(* Logix 5000 AddOnInstructionDefinition export AKD_Two_Axis_Move; software revision 19.01; part 2 of 3 *)

ADD_ON_INSTRUCTION AKD_Set_Position   (* revision 2.1, ExecutePrescan, ExecuteEnableInFalse *)
// Set Drive Position
// Revision note:
// Don't error if Command_Timeout preset is 0
VAR_OUTPUT
   DN : BOOL; {access Read Only, visible}   // Command Successful
   ER : BOOL; {access Read Only, visible}   // Error
END_VAR
VAR_IN_OUT
   Axis : AKD_Axis; {required}
END_VAR
VAR_INPUT
   Incremental : BOOL; {visible}   // Position Definition (0=Absolute, 1=Incremental)
   Position : DINT; {required}   // Position Value
END_VAR
VAR_OUTPUT
   PC : BOOL; {access Read Only, visible}   // Process Complete
   IP : BOOL; {access Read Only, visible}   // In Process
END_VAR
VAR
   Response_Bytes : SINT[8];
   OS_LoadStart : BOOL;
   Position_Internal : DINT;   // Scaled Position Value for Drive
   Command_Timeout : TIMER := (PRE := 200);   // Timeout Timer
   Command_Message_Type : SINT;   // Command Message Type
   Command_Axis_Number : SINT;   // Command Axis Number
   Response_Message_Type : SINT;   // Response Message Type
   Response_Axis_Number : SINT;   // Response Axis Number
   Command_Bytes : SINT[8];
   Step : SINT;
END_VAR

ROUTINE EnableInFalse   (* ladder *)
// EnableIn_False
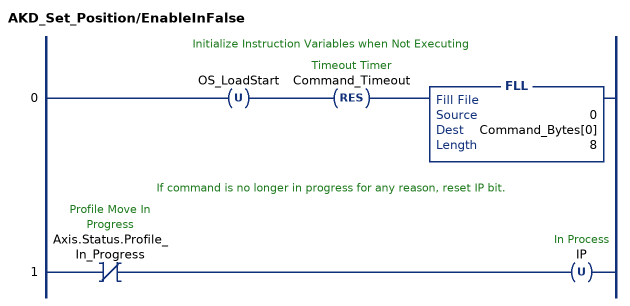
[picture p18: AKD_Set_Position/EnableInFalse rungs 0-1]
   // Initialize Instruction Variables when Not Executing
   0: OTU(OS_LoadStart)RES(Command_Timeout)FLL(0,Command_Bytes[0],8);
   // If command is no longer in progress for any reason, reset IP bit.
   1: XIO(Axis.Status.Profile_In_Progress)OTU(IP);
END_ROUTINE

ROUTINE Logic   (* ladder *)
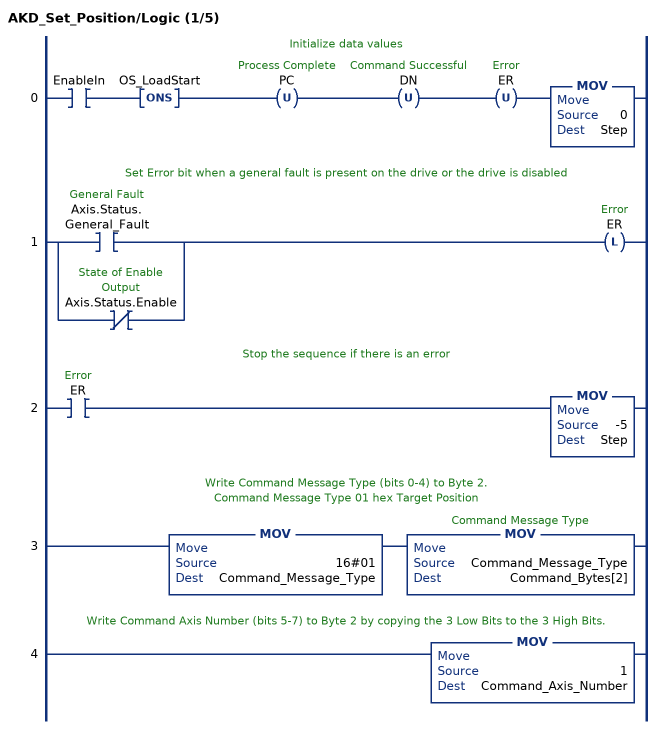
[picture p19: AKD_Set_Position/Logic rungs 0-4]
   // Initialize data values
   0: XIC(EnableIn)ONS(OS_LoadStart)OTU(PC)OTU(DN)OTU(ER)MOV(0,Step);
   // Set Error bit when a general fault is present on the drive or the drive is disabled
   1: [XIC(Axis.Status.General_Fault) ,XIO(Axis.Status.Enable) ]OTL(ER);
   // Stop the sequence if there is an error
   2: XIC(ER)MOV(-5,Step);
   // Write Command Message Type (bits 0-4) to Byte 2.
   // Command Message Type 01 hex Target Position
   3: MOV(16#01,Command_Message_Type)MOV(Command_Message_Type,Command_Bytes[2]);
   // Write Command Axis Number (bits 5-7) to Byte 2 by copying the 3 Low Bits to the 3 High Bits.
   4: MOV(1,Command_Axis_Number);
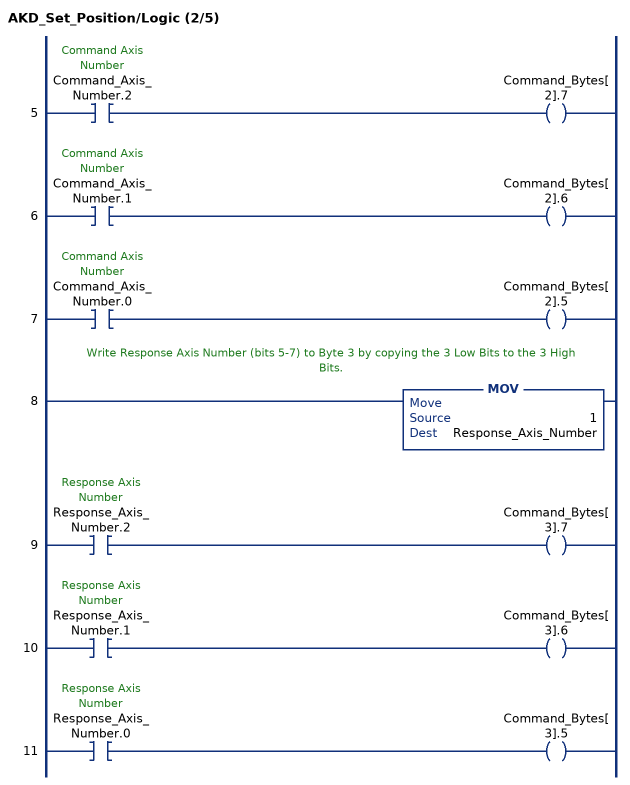
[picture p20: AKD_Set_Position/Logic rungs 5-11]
   5: XIC(Command_Axis_Number.2)OTE(Command_Bytes[2].7);
   6: XIC(Command_Axis_Number.1)OTE(Command_Bytes[2].6);
   7: XIC(Command_Axis_Number.0)OTE(Command_Bytes[2].5);
   // Write Response Axis Number (bits 5-7) to Byte 3 by copying the 3 Low Bits to the 3 High Bits.
   8: MOV(1,Response_Axis_Number);
   9: XIC(Response_Axis_Number.2)OTE(Command_Bytes[3].7);
   10: XIC(Response_Axis_Number.1)OTE(Command_Bytes[3].6);
   11: XIC(Response_Axis_Number.0)OTE(Command_Bytes[3].5);
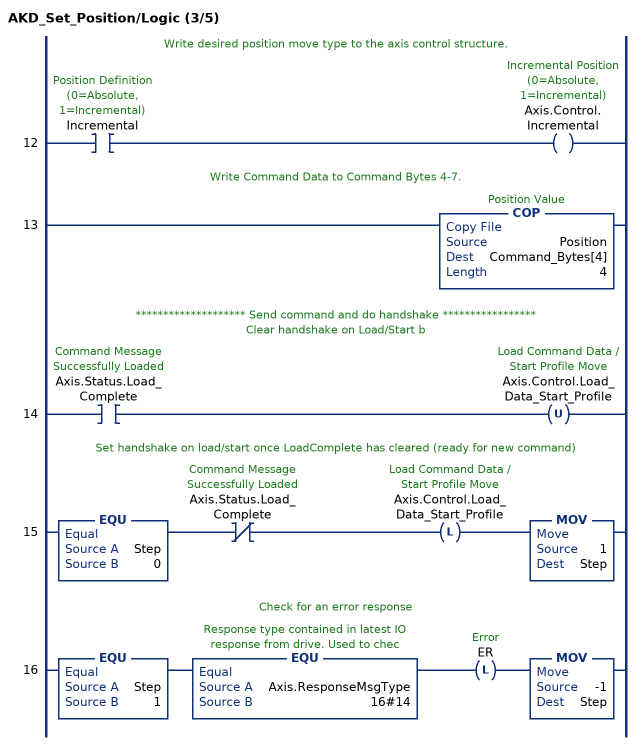
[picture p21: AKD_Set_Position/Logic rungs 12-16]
   // Write desired position move type to the axis control structure.
   12: XIC(Incremental)OTE(Axis.Control.Incremental);
   // Write Command Data to Command Bytes 4-7.
   13: COP(Position,Command_Bytes[4],4);
   // ******************** Send command and do handshake *****************
   // Clear handshake on Load/Start b
   14: XIC(Axis.Status.Load_Complete)OTU(Axis.Control.Load_Data_Start_Profile);
   // Set handshake on load/start once LoadComplete has cleared (ready for new command)
   15: EQU(Step,0)XIO(Axis.Status.Load_Complete)OTL(Axis.Control.Load_Data_Start_Profile)MOV(1,Step);
   // Check for an error response
   16: EQU(Step,1)EQU(Axis.ResponseMsgType,16#14)OTL(ER)MOV(-1,Step);
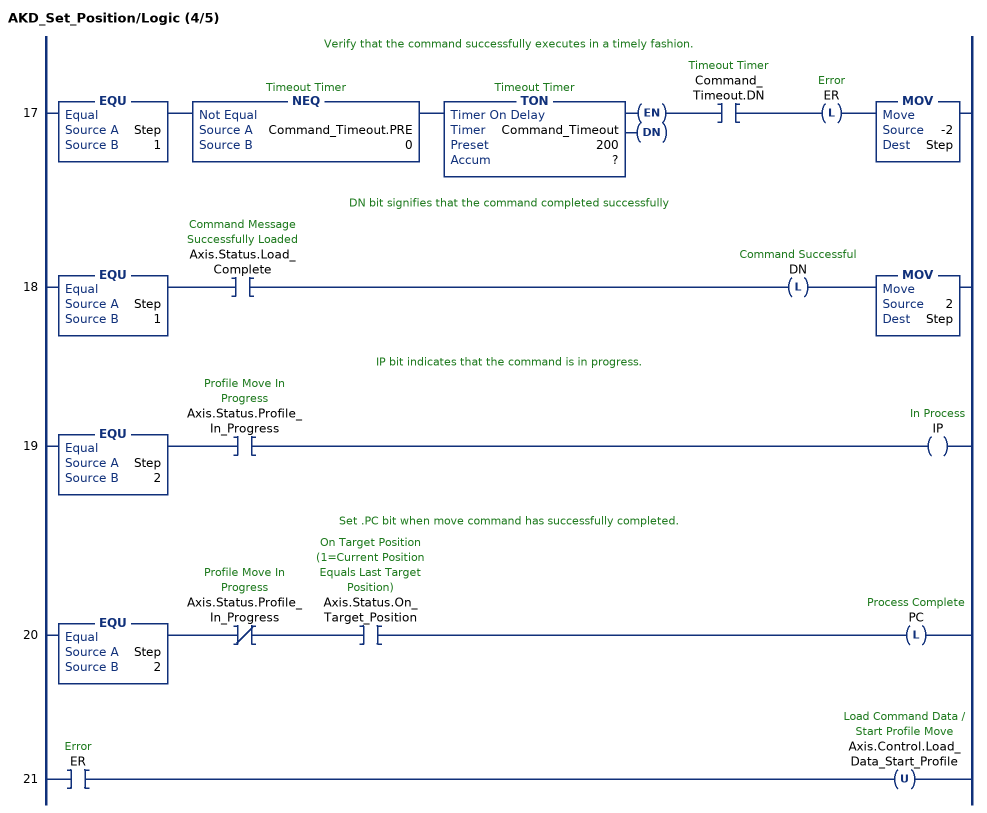
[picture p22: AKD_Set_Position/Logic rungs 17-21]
   // Verify that the command successfully executes in a timely fashion.
   17: EQU(Step,1)NEQ(Command_Timeout.PRE,0)TON(Command_Timeout,?,?)XIC(Command_Timeout.DN)OTL(ER)MOV(-2,Step);
   // DN bit signifies that the command completed successfully
   18: EQU(Step,1)XIC(Axis.Status.Load_Complete)OTL(DN)MOV(2,Step);
   // IP bit indicates that the command is in progress.
   19: EQU(Step,2)XIC(Axis.Status.Profile_In_Progress)OTE(IP);
   // Set .PC bit when move command has successfully completed.
   20: EQU(Step,2)XIO(Axis.Status.Profile_In_Progress)XIC(Axis.Status.On_Target_Position)OTL(PC);
   21: XIC(ER)OTU(Axis.Control.Load_Data_Start_Profile);
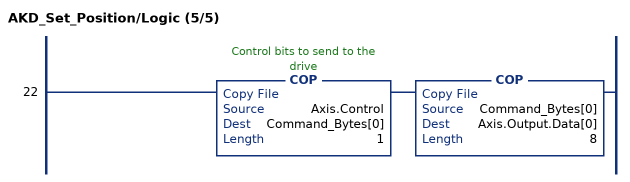
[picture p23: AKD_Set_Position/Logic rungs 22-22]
   22: COP(Axis.Control,Command_Bytes[0],1)COP(Command_Bytes[0],Axis.Output.Data[0],8);
END_ROUTINE

ROUTINE Prescan   (* ladder *)
// Prescan
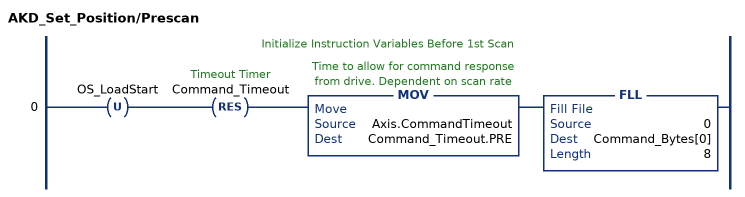
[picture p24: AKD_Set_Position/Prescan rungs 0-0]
   // Initialize Instruction Variables Before 1st Scan
   0: OTU(OS_LoadStart)RES(Command_Timeout)MOV(Axis.CommandTimeout,Command_Timeout.PRE)FLL(0,Command_Bytes[0],8);
END_ROUTINE
END_ADD_ON_INSTRUCTION

ADD_ON_INSTRUCTION AKD_Move   (* revision 3.1, ExecutePrescan, ExecuteEnableInFalse *)
// Motion Axis Move - Position Move
// Revision note:
// Don't error if Command_Timeout preset is 0
VAR_IN_OUT
   Axis : AKD_Axis; {required}
END_VAR
VAR_INPUT
   Move_Type : SINT; {required}   // Move Type (0=Absolute, 1=Incremental)
   Accel : DINT; {required}   // Acceleration
   Decel : DINT; {required}   // Deceleration
   Speed : DINT; {required}   // Move Speed
   Position : DINT; {required}   // Target Position
END_VAR
VAR_OUTPUT
   DN : BOOL; {access Read Only, visible}   // Command Successfully Initiated
   ER : BOOL; {access Read Only, visible}   // Error
   IP : BOOL; {access Read Only, visible}   // Command in Process
   PC : BOOL; {access Read Only, visible}   // Command Process Complete
END_VAR
VAR
   Step : SINT;   // Sequence Step Number
   Command_Axis_Number : SINT;
   Response_Axis_Number : SINT;
   Set_Accel : AKD_Set_Accel;
   Set_Decel : AKD_Set_Decel;
   Set_Velocity : AKD_Set_Velocity;
   OS_Start_Sequence : BOOL;
   Set_Position : AKD_Set_Position;
   Command_Timeout : TIMER := (PRE := 200);
   Command_Bytes : SINT[64];
   ErrorData : SINT[8];
END_VAR

ROUTINE EnableInFalse   (* ladder *)
// EnableIn_False
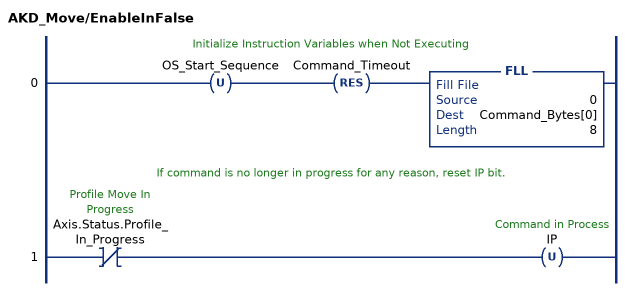
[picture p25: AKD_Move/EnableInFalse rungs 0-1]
   // Initialize Instruction Variables when Not Executing
   0: OTU(OS_Start_Sequence)RES(Command_Timeout)FLL(0,Command_Bytes[0],8);
   // If command is no longer in progress for any reason, reset IP bit.
   1: XIO(Axis.Status.Profile_In_Progress)OTU(IP);
END_ROUTINE

ROUTINE Logic   (* ladder *)
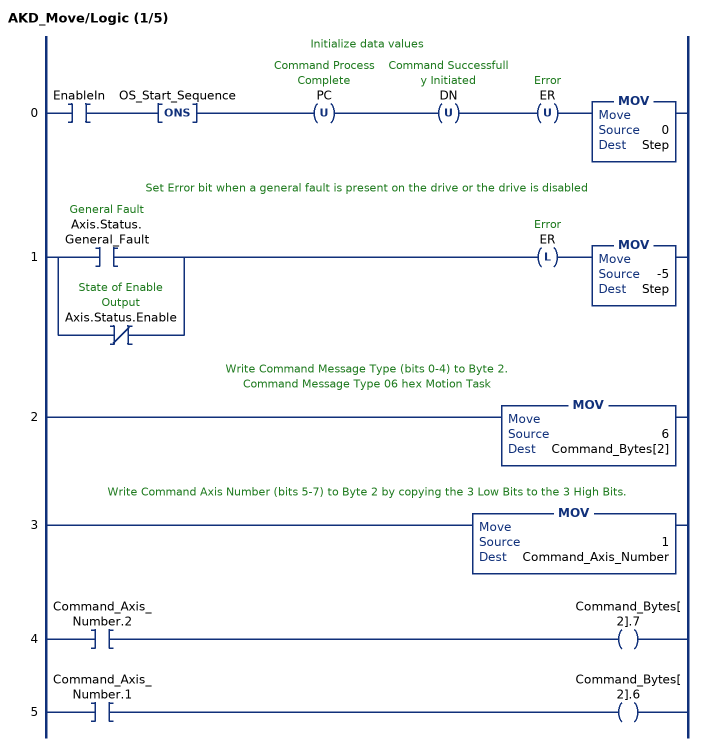
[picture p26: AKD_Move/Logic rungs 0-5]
   // Initialize data values
   0: XIC(EnableIn)ONS(OS_Start_Sequence)OTU(PC)OTU(DN)OTU(ER)MOV(0,Step);
   // Set Error bit when a general fault is present on the drive or the drive is disabled
   1: [XIC(Axis.Status.General_Fault) ,XIO(Axis.Status.Enable) ]OTL(ER)MOV(-5,Step);
   // Write Command Message Type (bits 0-4) to Byte 2.
   // Command Message Type 06 hex Motion Task
   2: MOV(6,Command_Bytes[2]);
   // Write Command Axis Number (bits 5-7) to Byte 2 by copying the 3 Low Bits to the 3 High Bits.
   3: MOV(1,Command_Axis_Number);
   4: XIC(Command_Axis_Number.2)OTE(Command_Bytes[2].7);
   5: XIC(Command_Axis_Number.1)OTE(Command_Bytes[2].6);
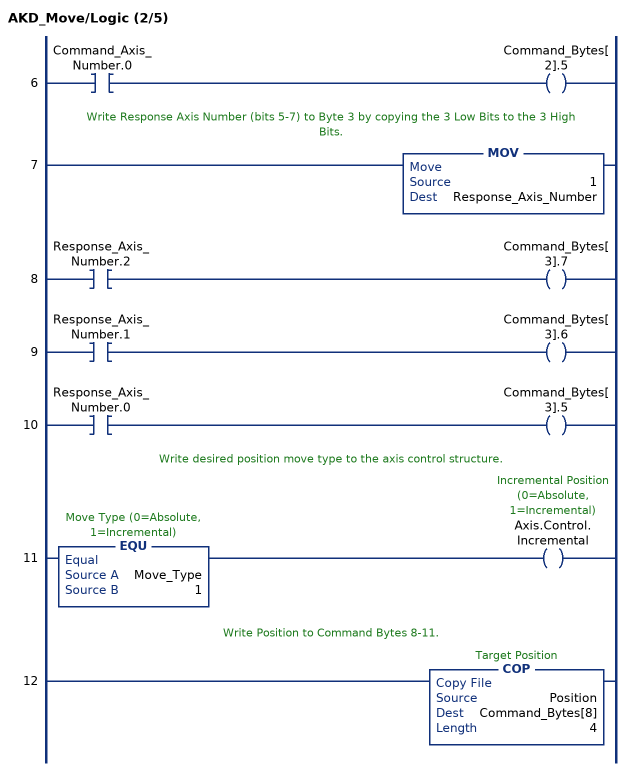
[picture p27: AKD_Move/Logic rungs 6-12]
   6: XIC(Command_Axis_Number.0)OTE(Command_Bytes[2].5);
   // Write Response Axis Number (bits 5-7) to Byte 3 by copying the 3 Low Bits to the 3 High Bits.
   7: MOV(1,Response_Axis_Number);
   8: XIC(Response_Axis_Number.2)OTE(Command_Bytes[3].7);
   9: XIC(Response_Axis_Number.1)OTE(Command_Bytes[3].6);
   10: XIC(Response_Axis_Number.0)OTE(Command_Bytes[3].5);
   // Write desired position move type to the axis control structure.
   11: EQU(Move_Type,1)OTE(Axis.Control.Incremental);
   // Write Position to Command Bytes 8-11.
   12: COP(Position,Command_Bytes[8],4);
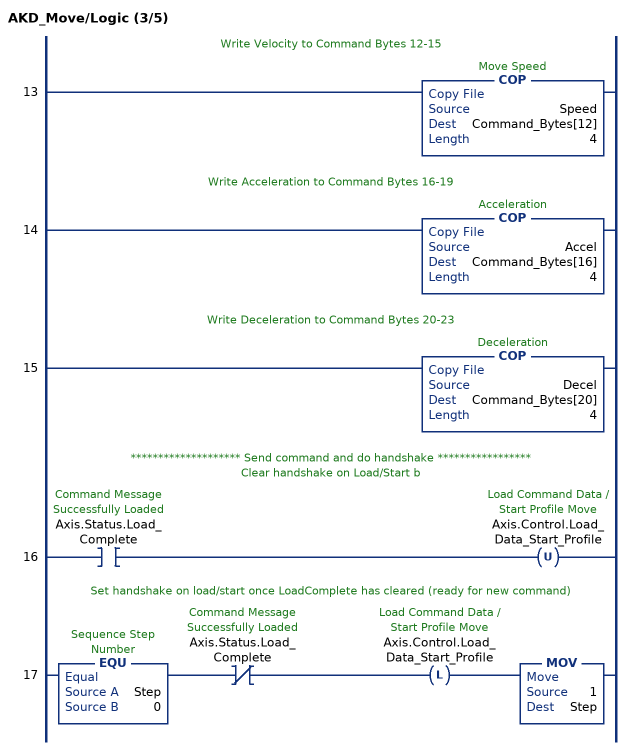
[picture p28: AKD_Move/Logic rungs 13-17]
   // Write Velocity to Command Bytes 12-15
   13: COP(Speed,Command_Bytes[12],4);
   // Write Acceleration to Command Bytes 16-19
   14: COP(Accel,Command_Bytes[16],4);
   // Write Deceleration to Command Bytes 20-23
   15: COP(Decel,Command_Bytes[20],4);
   // ******************** Send command and do handshake *****************
   // Clear handshake on Load/Start b
   16: XIC(Axis.Status.Load_Complete)OTU(Axis.Control.Load_Data_Start_Profile);
   // Set handshake on load/start once LoadComplete has cleared (ready for new command)
   17: EQU(Step,0)XIO(Axis.Status.Load_Complete)OTL(Axis.Control.Load_Data_Start_Profile)MOV(1,Step);
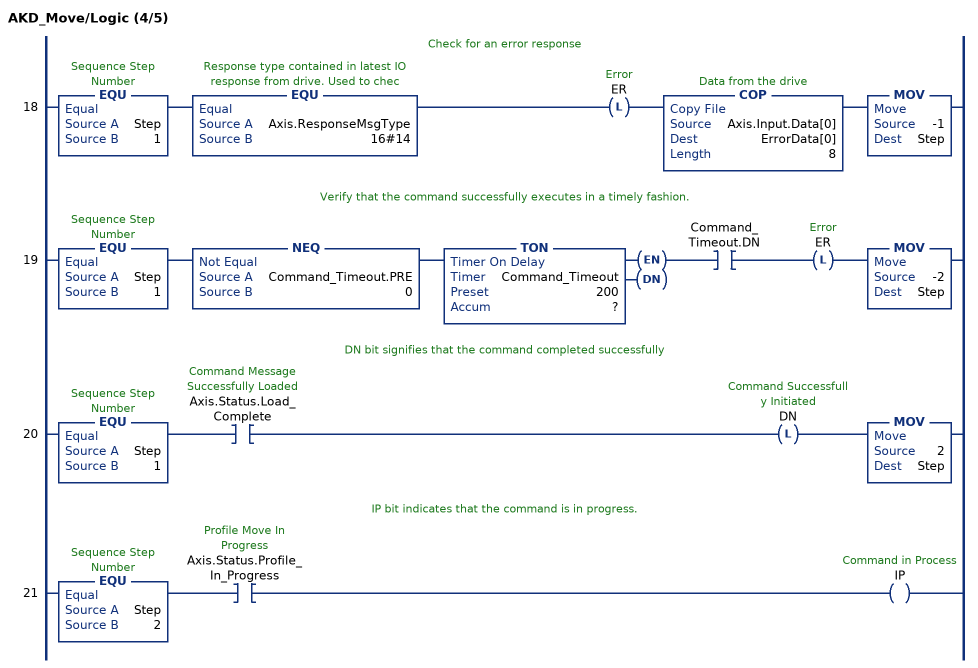
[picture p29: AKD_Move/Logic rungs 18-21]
   // Check for an error response
   18: EQU(Step,1)EQU(Axis.ResponseMsgType,16#14)OTL(ER)COP(Axis.Input.Data[0],ErrorData[0],8)MOV(-1,Step);
   // Verify that the command successfully executes in a timely fashion.
   19: EQU(Step,1)NEQ(Command_Timeout.PRE,0)TON(Command_Timeout,?,?)XIC(Command_Timeout.DN)OTL(ER)MOV(-2,Step);
   // DN bit signifies that the command completed successfully
   20: EQU(Step,1)XIC(Axis.Status.Load_Complete)OTL(DN)MOV(2,Step);
   // IP bit indicates that the command is in progress.
   21: EQU(Step,2)XIC(Axis.Status.Profile_In_Progress)OTE(IP);
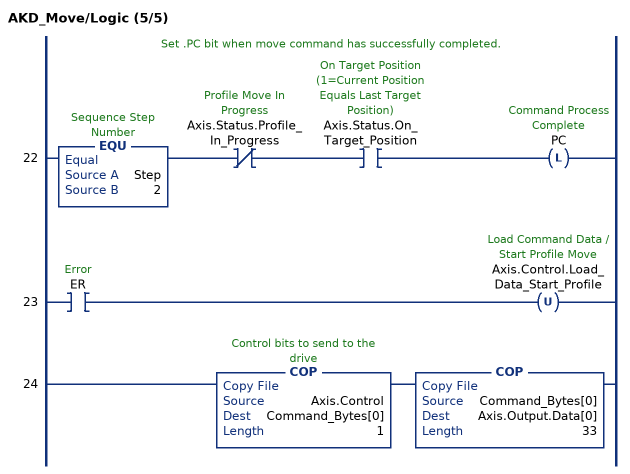
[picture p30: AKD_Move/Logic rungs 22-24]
   // Set .PC bit when move command has successfully completed.
   22: EQU(Step,2)XIO(Axis.Status.Profile_In_Progress)XIC(Axis.Status.On_Target_Position)OTL(PC);
   23: XIC(ER)OTU(Axis.Control.Load_Data_Start_Profile);
   24: COP(Axis.Control,Command_Bytes[0],1)COP(Command_Bytes[0],Axis.Output.Data[0],33);
END_ROUTINE

ROUTINE Prescan   (* ladder *)
// Prescan
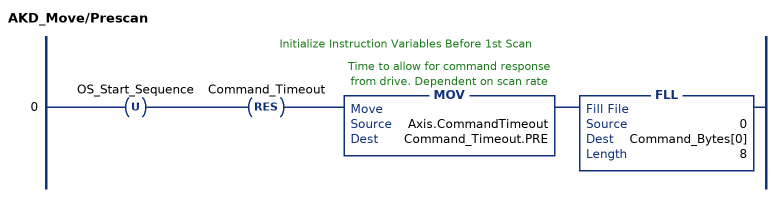
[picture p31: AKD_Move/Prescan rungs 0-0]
   // Initialize Instruction Variables Before 1st Scan
   0: OTU(OS_Start_Sequence)RES(Command_Timeout)MOV(Axis.CommandTimeout,Command_Timeout.PRE)FLL(0,Command_Bytes[0],8);
END_ROUTINE
END_ADD_ON_INSTRUCTION

ADD_ON_INSTRUCTION AKD_Two_Axis_Move   (* revision 1.0, ExecuteEnableInFalse *)
VAR_OUTPUT
   DN : BOOL; {visible}   // Command sent to drive
   IP : BOOL; {visible}   // Move In Process
   PC : BOOL; {visible}   // Move complete received
   ER : BOOL; {visible}   // ERROR IN MOVE
END_VAR
VAR_IN_OUT
   X_Module : AKD_Axis; {required}
   Y_Module : AKD_Axis; {required}
END_VAR
VAR_INPUT
   X_Targ_Pos : DINT; {required}   // X Axis Target Position
   Y_Targ_Pos : DINT; {required}   // Y Axis Target Position
   Linear_ACC : DINT; {required}   // Linear Motion ACC
   Linear_DEC : DINT; {required}   // Linear Motion DEC
   Linear_VEL : DINT; {required}   // Linear Velocity
   Motion_Type : DINT; {required}   // Absolute = 0, Relative = 1
END_VAR
VAR
   Int_1_sht : BOOL; {access None}
   X_Axis : AKD_Move; {access None}
   Start_Move : BOOL; {access None}
   X_1_sht : BOOL; {access None}
   Axis_1 : AKD_Axis; {access None}
   X_Move_Type : SINT; {access None}
   y_Move_Type : SINT; {access None}
   X_ACC : DINT; {access None}
   X_DEC : DINT; {access None}
   X_VEL : DINT; {access None}
   Y_1_sht : BOOL; {access None}
   Y_Axis : AKD_Move; {access None}
   Axis_2 : AKD_Axis; {access None}
   Y_ACC : DINT; {access None}
   Y_DEC : DINT; {access None}
   Y_VEL : DINT; {access None}
   Function_Step : DINT; {access None}
   Start_X_Pos : DINT; {access None}
   Start_Y_Pos : DINT; {access None}
   X_Move_Dist : DINT; {access None}
   Y_Move_Dist : REAL; {access None}
   X_Dist_SQ : REAL; {access None}
   DINT : LINT; {access None}
   Y_Dist_SQ : REAL; {access None}
   Long_X_Dist : REAL; {access None}
   Long_y_Dist : REAL; {access None}
   Total_Dist_SQ : REAL; {access None}
   Total_Dist_Slope : REAL; {access None}
   X_Multiplier : REAL; {access None}
   Y_Multiplier : REAL; {access None}
   XY_Slope : REAL; {access None}
   YX_Slope : REAL; {access None}
   Begin : BOOL; {access None}
   XY_SQ_SUM : REAL; {access None}
   XY_RMS : REAL; {access None}
   INV_XY_RMS : REAL; {access None}
   Running : BOOL; {access None}
   Time_1 : TIMER := (PRE := 50); {access None}
   Temp_Time : TIMER := (PRE := 20); {access None}
   Kick_Off_Move : BOOL; {access None}
   ONE_SCAN : BOOL; {access None}
   Delay_Pause : TIMER := (PRE := 20); {access None}
END_VAR

ROUTINE EnableInFalse   (* ladder *)
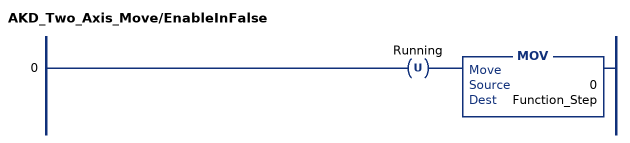
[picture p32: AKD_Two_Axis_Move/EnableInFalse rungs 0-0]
   0: OTU(Running)MOV(0,Function_Step);
END_ROUTINE

ROUTINE Logic   (* ladder *)
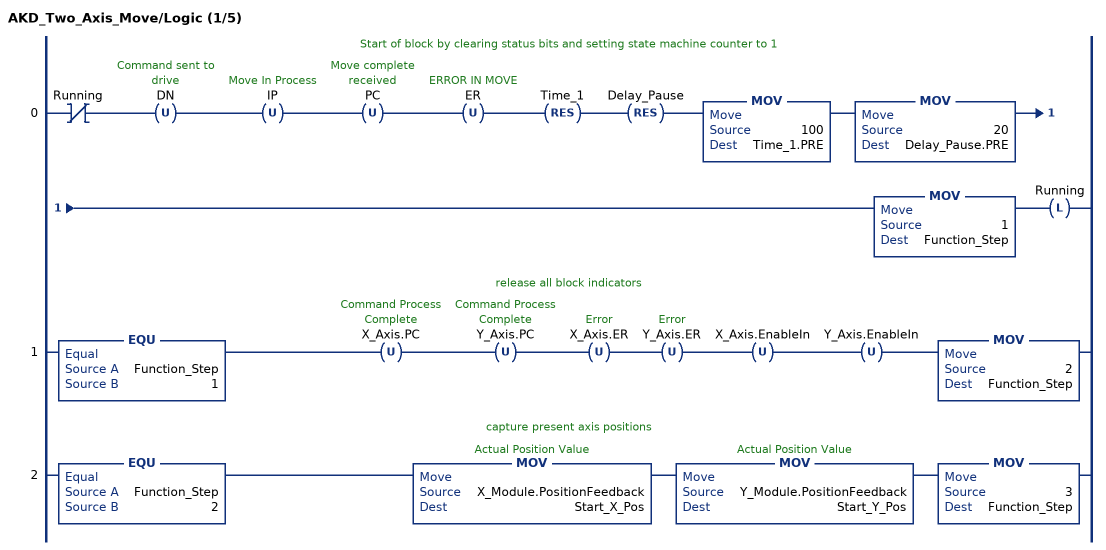
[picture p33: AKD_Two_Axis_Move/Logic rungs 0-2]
   // Start of block by clearing status bits and setting state machine counter to 1
   0: XIO(Running)OTU(DN)OTU(IP)OTU(PC)OTU(ER)RES(Time_1)RES(Delay_Pause)MOV(100,Time_1.PRE)MOV(20,Delay_Pause.PRE)MOV(1,Function_Step)OTL(Running);
   // release all block indicators
   1: EQU(Function_Step,1)OTU(X_Axis.PC)OTU(Y_Axis.PC)OTU(X_Axis.ER)OTU(Y_Axis.ER)OTU(X_Axis.EnableIn)OTU(Y_Axis.EnableIn)MOV(2,Function_Step);
   // capture present axis positions
   2: EQU(Function_Step,2)MOV(X_Module.PositionFeedback,Start_X_Pos)MOV(Y_Module.PositionFeedback,Start_Y_Pos)MOV(3,Function_Step);
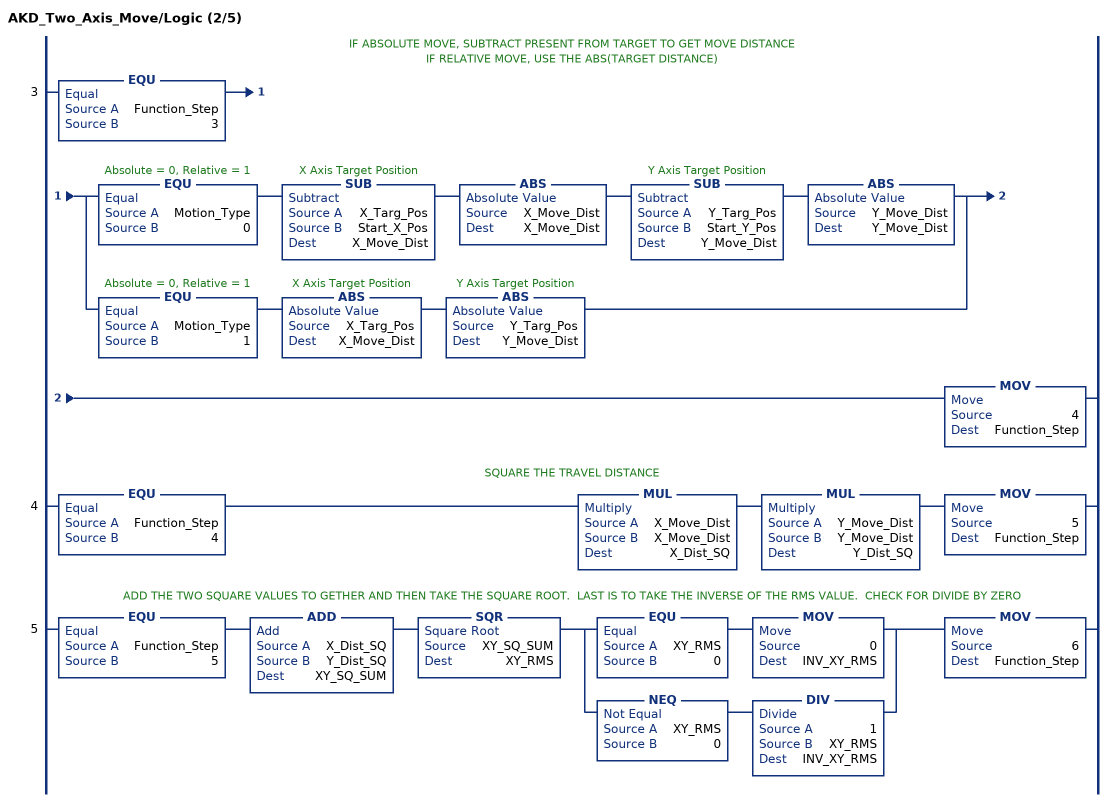
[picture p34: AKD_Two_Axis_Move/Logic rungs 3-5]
   // IF ABSOLUTE MOVE, SUBTRACT PRESENT FROM TARGET TO GET MOVE DISTANCE
   // IF RELATIVE MOVE, USE THE ABS(TARGET DISTANCE)
   3: EQU(Function_Step,3)[EQU(Motion_Type,0) SUB(X_Targ_Pos,Start_X_Pos,X_Move_Dist) ABS(X_Move_Dist,X_Move_Dist) SUB(Y_Targ_Pos,Start_Y_Pos,Y_Move_Dist) ABS(Y_Move_Dist,Y_Move_Dist) ,EQU(Motion_Type,1) ABS(X_Targ_Pos,X_Move_Dist) ABS(Y_Targ_Pos,Y_Move_Dist) ]MOV(4,Function_Step);
   // SQUARE THE TRAVEL DISTANCE
   4: EQU(Function_Step,4)MUL(X_Move_Dist,X_Move_Dist,X_Dist_SQ)MUL(Y_Move_Dist,Y_Move_Dist,Y_Dist_SQ)MOV(5,Function_Step);
   // ADD THE TWO SQUARE VALUES TO GETHER AND THEN TAKE THE SQUARE ROOT.  LAST IS TO TAKE THE INVERSE OF THE RMS VALUE.  CHECK FOR DIVIDE BY ZERO
   5: EQU(Function_Step,5)ADD(X_Dist_SQ,Y_Dist_SQ,XY_SQ_SUM)SQR(XY_SQ_SUM,XY_RMS)[EQU(XY_RMS,0) MOV(0,INV_XY_RMS) ,NEQ(XY_RMS,0) DIV(1,XY_RMS,INV_XY_RMS) ]MOV(6,Function_Step);
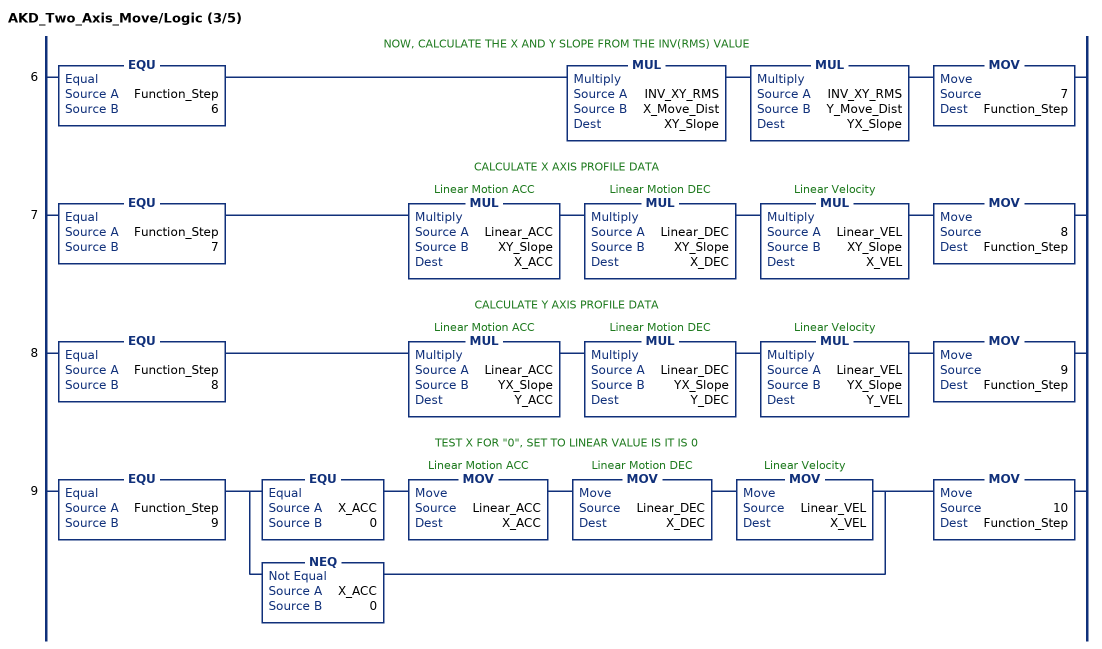
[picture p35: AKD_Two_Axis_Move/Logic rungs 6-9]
   // NOW, CALCULATE THE X AND Y SLOPE FROM THE INV(RMS) VALUE
   6: EQU(Function_Step,6)MUL(INV_XY_RMS,X_Move_Dist,XY_Slope)MUL(INV_XY_RMS,Y_Move_Dist,YX_Slope)MOV(7,Function_Step);
   // CALCULATE X AXIS PROFILE DATA
   7: EQU(Function_Step,7)MUL(Linear_ACC,XY_Slope,X_ACC)MUL(Linear_DEC,XY_Slope,X_DEC)MUL(Linear_VEL,XY_Slope,X_VEL)MOV(8,Function_Step);
   // CALCULATE Y AXIS PROFILE DATA
   8: EQU(Function_Step,8)MUL(Linear_ACC,YX_Slope,Y_ACC)MUL(Linear_DEC,YX_Slope,Y_DEC)MUL(Linear_VEL,YX_Slope,Y_VEL)MOV(9,Function_Step);
   // TEST X FOR "0", SET TO LINEAR VALUE IS IT IS 0
   9: EQU(Function_Step,9)[EQU(X_ACC,0) MOV(Linear_ACC,X_ACC) MOV(Linear_DEC,X_DEC) MOV(Linear_VEL,X_VEL) ,NEQ(X_ACC,0) ]MOV(10,Function_Step);
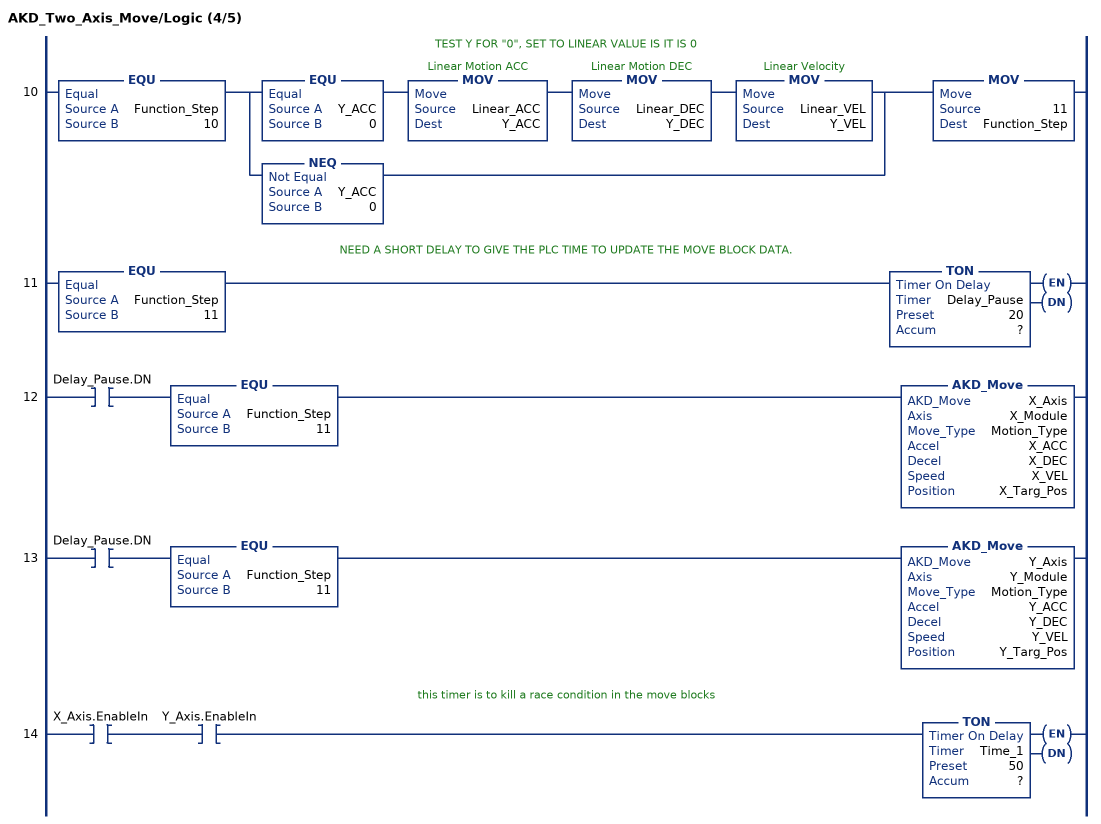
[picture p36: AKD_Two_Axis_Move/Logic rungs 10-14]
   // TEST Y FOR "0", SET TO LINEAR VALUE IS IT IS 0
   10: EQU(Function_Step,10)[EQU(Y_ACC,0) MOV(Linear_ACC,Y_ACC) MOV(Linear_DEC,Y_DEC) MOV(Linear_VEL,Y_VEL) ,NEQ(Y_ACC,0) ]MOV(11,Function_Step);
   // NEED A SHORT DELAY TO GIVE THE PLC TIME TO UPDATE THE MOVE BLOCK DATA.
   11: EQU(Function_Step,11)TON(Delay_Pause,?,?);
   12: XIC(Delay_Pause.DN)EQU(Function_Step,11)AKD_Move(X_Axis,X_Module,Motion_Type,X_ACC,X_DEC,X_VEL,X_Targ_Pos);
   13: XIC(Delay_Pause.DN)EQU(Function_Step,11)AKD_Move(Y_Axis,Y_Module,Motion_Type,Y_ACC,Y_DEC,Y_VEL,Y_Targ_Pos);
   // this timer is to kill a race condition in the move blocks
   14: XIC(X_Axis.EnableIn)XIC(Y_Axis.EnableIn)TON(Time_1,?,?);
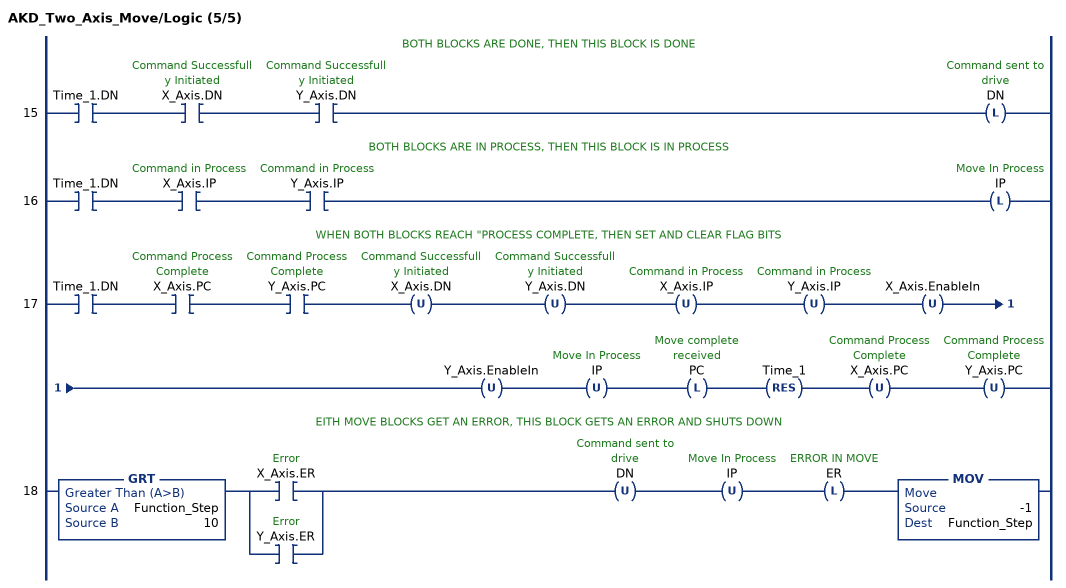
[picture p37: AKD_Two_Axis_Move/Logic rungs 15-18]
   // BOTH BLOCKS ARE DONE, THEN THIS BLOCK IS DONE
   15: XIC(Time_1.DN)XIC(X_Axis.DN)XIC(Y_Axis.DN)OTL(DN);
   // BOTH BLOCKS ARE IN PROCESS, THEN THIS BLOCK IS IN PROCESS
   16: XIC(Time_1.DN)XIC(X_Axis.IP)XIC(Y_Axis.IP)OTL(IP);
   // WHEN BOTH BLOCKS REACH "PROCESS COMPLETE, THEN SET AND CLEAR FLAG BITS
   17: XIC(Time_1.DN)XIC(X_Axis.PC)XIC(Y_Axis.PC)OTU(X_Axis.DN)OTU(Y_Axis.DN)OTU(X_Axis.IP)OTU(Y_Axis.IP)OTU(X_Axis.EnableIn)OTU(Y_Axis.EnableIn)OTU(IP)OTL(PC)RES(Time_1)OTU(X_Axis.PC)OTU(Y_Axis.PC);
   // EITH MOVE BLOCKS GET AN ERROR, THIS BLOCK GETS AN ERROR AND SHUTS DOWN
   18: GRT(Function_Step,10)[XIC(X_Axis.ER) ,XIC(Y_Axis.ER) ]OTU(DN)OTU(IP)OTL(ER)MOV(-1,Function_Step);
END_ROUTINE
